VERSION 5.8 ;
BUSBITCHARS "[]" ;
DIVIDERCHAR "/" ;

UNITS
  DATABASE MICRONS 1000 ;
END UNITS

MANUFACTURINGGRID 0.001 ;

SITE asap7sc7p5t
  CLASS CORE ;
  SYMMETRY Y ;
  SIZE 0.054 BY 0.27 ;
END asap7sc7p5t

# ---- RVT filler cells ----
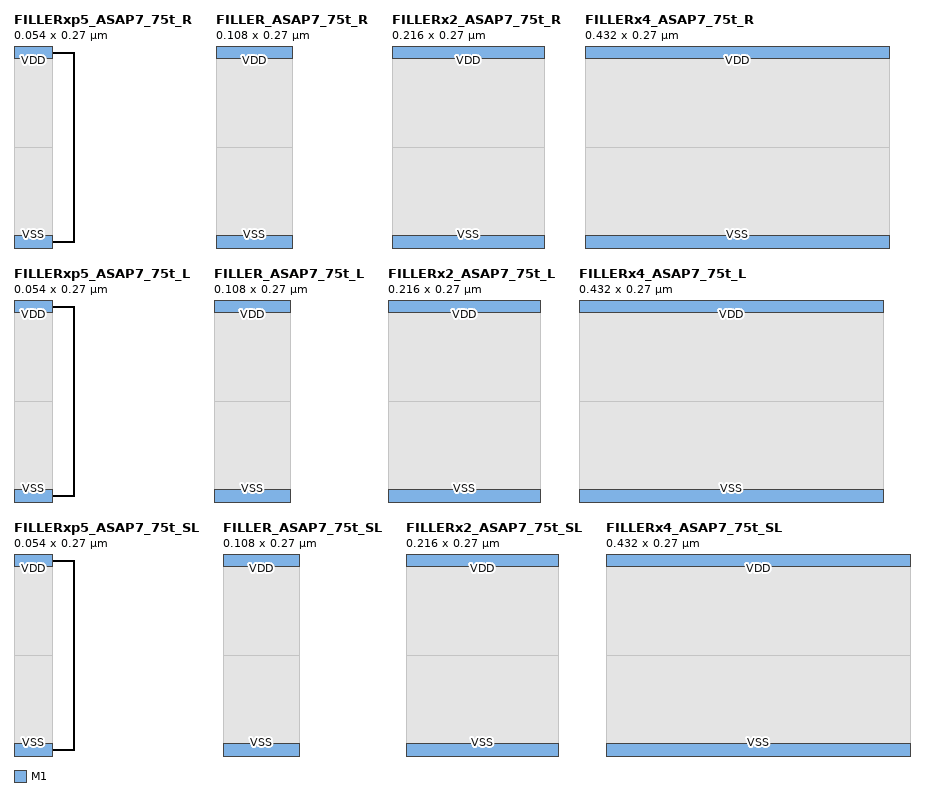
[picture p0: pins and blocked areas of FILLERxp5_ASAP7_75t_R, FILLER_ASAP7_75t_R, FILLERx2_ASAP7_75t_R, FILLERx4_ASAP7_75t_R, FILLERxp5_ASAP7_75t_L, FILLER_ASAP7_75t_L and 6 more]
MACRO FILLERxp5_ASAP7_75t_R
  CLASS CORE SPACER ;
  ORIGIN 0 0 ;
  SIZE 0.054 BY 0.27 ;
  SYMMETRY X Y ;
  SITE asap7sc7p5t ;
  PIN VDD
    DIRECTION INOUT ;
    USE POWER ;
    SHAPE ABUTMENT ;
    PORT
      LAYER M1 ;
        RECT 0 0.261 0.054 0.279 ;
    END
  END VDD
  PIN VSS
    DIRECTION INOUT ;
    USE GROUND ;
    SHAPE ABUTMENT ;
    PORT
      LAYER M1 ;
        RECT 0 -0.009 0.054 0.009 ;
    END
  END VSS
  OBS
    LAYER RVTN ;
      RECT 0 0 0.054 0.135 ;
    LAYER RVTP ;
      RECT 0 0.135 0.054 0.27 ;
  END
END FILLERxp5_ASAP7_75t_R

MACRO FILLER_ASAP7_75t_R
  CLASS CORE SPACER ;
  ORIGIN 0 0 ;
  SIZE 0.108 BY 0.27 ;
  SYMMETRY X Y ;
  SITE asap7sc7p5t ;
  PIN VDD
    DIRECTION INOUT ;
    USE POWER ;
    SHAPE ABUTMENT ;
    PORT
      LAYER M1 ;
        RECT 0 0.261 0.108 0.279 ;
    END
  END VDD
  PIN VSS
    DIRECTION INOUT ;
    USE GROUND ;
    SHAPE ABUTMENT ;
    PORT
      LAYER M1 ;
        RECT 0 -0.009 0.108 0.009 ;
    END
  END VSS
  OBS
    LAYER RVTN ;
      RECT 0 0 0.108 0.135 ;
    LAYER RVTP ;
      RECT 0 0.135 0.108 0.27 ;
  END
END FILLER_ASAP7_75t_R

MACRO FILLERx2_ASAP7_75t_R
  CLASS CORE SPACER ;
  ORIGIN 0 0 ;
  SIZE 0.216 BY 0.27 ;
  SYMMETRY X Y ;
  SITE asap7sc7p5t ;
  PIN VDD
    DIRECTION INOUT ;
    USE POWER ;
    SHAPE ABUTMENT ;
    PORT
      LAYER M1 ;
        RECT 0 0.261 0.216 0.279 ;
    END
  END VDD
  PIN VSS
    DIRECTION INOUT ;
    USE GROUND ;
    SHAPE ABUTMENT ;
    PORT
      LAYER M1 ;
        RECT 0 -0.009 0.216 0.009 ;
    END
  END VSS
  OBS
    LAYER RVTN ;
      RECT 0 0 0.216 0.135 ;
    LAYER RVTP ;
      RECT 0 0.135 0.216 0.27 ;
  END
END FILLERx2_ASAP7_75t_R

MACRO FILLERx4_ASAP7_75t_R
  CLASS CORE SPACER ;
  ORIGIN 0 0 ;
  SIZE 0.432 BY 0.27 ;
  SYMMETRY X Y ;
  SITE asap7sc7p5t ;
  PIN VDD
    DIRECTION INOUT ;
    USE POWER ;
    SHAPE ABUTMENT ;
    PORT
      LAYER M1 ;
        RECT 0 0.261 0.432 0.279 ;
    END
  END VDD
  PIN VSS
    DIRECTION INOUT ;
    USE GROUND ;
    SHAPE ABUTMENT ;
    PORT
      LAYER M1 ;
        RECT 0 -0.009 0.432 0.009 ;
    END
  END VSS
  OBS
    LAYER RVTN ;
      RECT 0 0 0.432 0.135 ;
    LAYER RVTP ;
      RECT 0 0.135 0.432 0.27 ;
  END
END FILLERx4_ASAP7_75t_R

# ---- LVT filler cells ----
MACRO FILLERxp5_ASAP7_75t_L
  CLASS CORE SPACER ;
  ORIGIN 0 0 ;
  SIZE 0.054 BY 0.27 ;
  SYMMETRY X Y ;
  SITE asap7sc7p5t ;
  PIN VDD
    DIRECTION INOUT ;
    USE POWER ;
    SHAPE ABUTMENT ;
    PORT
      LAYER M1 ;
        RECT 0 0.261 0.054 0.279 ;
    END
  END VDD
  PIN VSS
    DIRECTION INOUT ;
    USE GROUND ;
    SHAPE ABUTMENT ;
    PORT
      LAYER M1 ;
        RECT 0 -0.009 0.054 0.009 ;
    END
  END VSS
  OBS
    LAYER LVTN ;
      RECT 0 0 0.054 0.135 ;
    LAYER LVTP ;
      RECT 0 0.135 0.054 0.27 ;
  END
END FILLERxp5_ASAP7_75t_L

MACRO FILLER_ASAP7_75t_L
  CLASS CORE SPACER ;
  ORIGIN 0 0 ;
  SIZE 0.108 BY 0.27 ;
  SYMMETRY X Y ;
  SITE asap7sc7p5t ;
  PIN VDD
    DIRECTION INOUT ;
    USE POWER ;
    SHAPE ABUTMENT ;
    PORT
      LAYER M1 ;
        RECT 0 0.261 0.108 0.279 ;
    END
  END VDD
  PIN VSS
    DIRECTION INOUT ;
    USE GROUND ;
    SHAPE ABUTMENT ;
    PORT
      LAYER M1 ;
        RECT 0 -0.009 0.108 0.009 ;
    END
  END VSS
  OBS
    LAYER LVTN ;
      RECT 0 0 0.108 0.135 ;
    LAYER LVTP ;
      RECT 0 0.135 0.108 0.27 ;
  END
END FILLER_ASAP7_75t_L

MACRO FILLERx2_ASAP7_75t_L
  CLASS CORE SPACER ;
  ORIGIN 0 0 ;
  SIZE 0.216 BY 0.27 ;
  SYMMETRY X Y ;
  SITE asap7sc7p5t ;
  PIN VDD
    DIRECTION INOUT ;
    USE POWER ;
    SHAPE ABUTMENT ;
    PORT
      LAYER M1 ;
        RECT 0 0.261 0.216 0.279 ;
    END
  END VDD
  PIN VSS
    DIRECTION INOUT ;
    USE GROUND ;
    SHAPE ABUTMENT ;
    PORT
      LAYER M1 ;
        RECT 0 -0.009 0.216 0.009 ;
    END
  END VSS
  OBS
    LAYER LVTN ;
      RECT 0 0 0.216 0.135 ;
    LAYER LVTP ;
      RECT 0 0.135 0.216 0.27 ;
  END
END FILLERx2_ASAP7_75t_L

MACRO FILLERx4_ASAP7_75t_L
  CLASS CORE SPACER ;
  ORIGIN 0 0 ;
  SIZE 0.432 BY 0.27 ;
  SYMMETRY X Y ;
  SITE asap7sc7p5t ;
  PIN VDD
    DIRECTION INOUT ;
    USE POWER ;
    SHAPE ABUTMENT ;
    PORT
      LAYER M1 ;
        RECT 0 0.261 0.432 0.279 ;
    END
  END VDD
  PIN VSS
    DIRECTION INOUT ;
    USE GROUND ;
    SHAPE ABUTMENT ;
    PORT
      LAYER M1 ;
        RECT 0 -0.009 0.432 0.009 ;
    END
  END VSS
  OBS
    LAYER LVTN ;
      RECT 0 0 0.432 0.135 ;
    LAYER LVTP ;
      RECT 0 0.135 0.432 0.27 ;
  END
END FILLERx4_ASAP7_75t_L

# ---- SLVT filler cells ----
MACRO FILLERxp5_ASAP7_75t_SL
  CLASS CORE SPACER ;
  ORIGIN 0 0 ;
  SIZE 0.054 BY 0.27 ;
  SYMMETRY X Y ;
  SITE asap7sc7p5t ;
  PIN VDD
    DIRECTION INOUT ;
    USE POWER ;
    SHAPE ABUTMENT ;
    PORT
      LAYER M1 ;
        RECT 0 0.261 0.054 0.279 ;
    END
  END VDD
  PIN VSS
    DIRECTION INOUT ;
    USE GROUND ;
    SHAPE ABUTMENT ;
    PORT
      LAYER M1 ;
        RECT 0 -0.009 0.054 0.009 ;
    END
  END VSS
  OBS
    LAYER SLVTN ;
      RECT 0 0 0.054 0.135 ;
    LAYER SLVTP ;
      RECT 0 0.135 0.054 0.27 ;
  END
END FILLERxp5_ASAP7_75t_SL

MACRO FILLER_ASAP7_75t_SL
  CLASS CORE SPACER ;
  ORIGIN 0 0 ;
  SIZE 0.108 BY 0.27 ;
  SYMMETRY X Y ;
  SITE asap7sc7p5t ;
  PIN VDD
    DIRECTION INOUT ;
    USE POWER ;
    SHAPE ABUTMENT ;
    PORT
      LAYER M1 ;
        RECT 0 0.261 0.108 0.279 ;
    END
  END VDD
  PIN VSS
    DIRECTION INOUT ;
    USE GROUND ;
    SHAPE ABUTMENT ;
    PORT
      LAYER M1 ;
        RECT 0 -0.009 0.108 0.009 ;
    END
  END VSS
  OBS
    LAYER SLVTN ;
      RECT 0 0 0.108 0.135 ;
    LAYER SLVTP ;
      RECT 0 0.135 0.108 0.27 ;
  END
END FILLER_ASAP7_75t_SL

MACRO FILLERx2_ASAP7_75t_SL
  CLASS CORE SPACER ;
  ORIGIN 0 0 ;
  SIZE 0.216 BY 0.27 ;
  SYMMETRY X Y ;
  SITE asap7sc7p5t ;
  PIN VDD
    DIRECTION INOUT ;
    USE POWER ;
    SHAPE ABUTMENT ;
    PORT
      LAYER M1 ;
        RECT 0 0.261 0.216 0.279 ;
    END
  END VDD
  PIN VSS
    DIRECTION INOUT ;
    USE GROUND ;
    SHAPE ABUTMENT ;
    PORT
      LAYER M1 ;
        RECT 0 -0.009 0.216 0.009 ;
    END
  END VSS
  OBS
    LAYER SLVTN ;
      RECT 0 0 0.216 0.135 ;
    LAYER SLVTP ;
      RECT 0 0.135 0.216 0.27 ;
  END
END FILLERx2_ASAP7_75t_SL

MACRO FILLERx4_ASAP7_75t_SL
  CLASS CORE SPACER ;
  ORIGIN 0 0 ;
  SIZE 0.432 BY 0.27 ;
  SYMMETRY X Y ;
  SITE asap7sc7p5t ;
  PIN VDD
    DIRECTION INOUT ;
    USE POWER ;
    SHAPE ABUTMENT ;
    PORT
      LAYER M1 ;
        RECT 0 0.261 0.432 0.279 ;
    END
  END VDD
  PIN VSS
    DIRECTION INOUT ;
    USE GROUND ;
    SHAPE ABUTMENT ;
    PORT
      LAYER M1 ;
        RECT 0 -0.009 0.432 0.009 ;
    END
  END VSS
  OBS
    LAYER SLVTN ;
      RECT 0 0 0.432 0.135 ;
    LAYER SLVTP ;
      RECT 0 0.135 0.432 0.27 ;
  END
END FILLERx4_ASAP7_75t_SL

# ---- ULVT filler cells ----
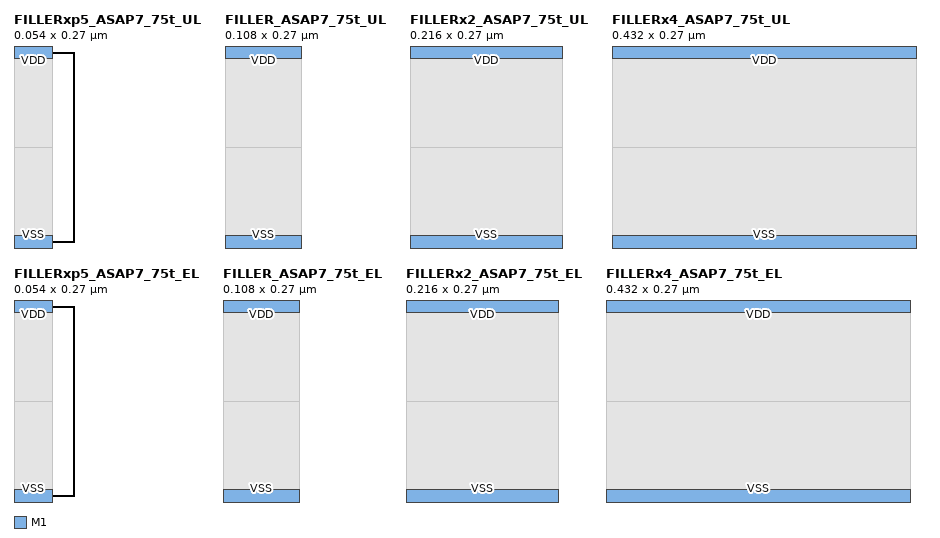
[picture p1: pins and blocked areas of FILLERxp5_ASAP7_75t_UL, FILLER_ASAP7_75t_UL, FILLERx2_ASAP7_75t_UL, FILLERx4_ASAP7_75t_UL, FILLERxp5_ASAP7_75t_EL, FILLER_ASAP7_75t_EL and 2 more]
MACRO FILLERxp5_ASAP7_75t_UL
  CLASS CORE SPACER ;
  ORIGIN 0 0 ;
  SIZE 0.054 BY 0.27 ;
  SYMMETRY X Y ;
  SITE asap7sc7p5t ;
  PIN VDD
    DIRECTION INOUT ;
    USE POWER ;
    SHAPE ABUTMENT ;
    PORT
      LAYER M1 ;
        RECT 0 0.261 0.054 0.279 ;
    END
  END VDD
  PIN VSS
    DIRECTION INOUT ;
    USE GROUND ;
    SHAPE ABUTMENT ;
    PORT
      LAYER M1 ;
        RECT 0 -0.009 0.054 0.009 ;
    END
  END VSS
  OBS
    LAYER ULVTN ;
      RECT 0 0 0.054 0.135 ;
    LAYER ULVTP ;
      RECT 0 0.135 0.054 0.27 ;
  END
END FILLERxp5_ASAP7_75t_UL

MACRO FILLER_ASAP7_75t_UL
  CLASS CORE SPACER ;
  ORIGIN 0 0 ;
  SIZE 0.108 BY 0.27 ;
  SYMMETRY X Y ;
  SITE asap7sc7p5t ;
  PIN VDD
    DIRECTION INOUT ;
    USE POWER ;
    SHAPE ABUTMENT ;
    PORT
      LAYER M1 ;
        RECT 0 0.261 0.108 0.279 ;
    END
  END VDD
  PIN VSS
    DIRECTION INOUT ;
    USE GROUND ;
    SHAPE ABUTMENT ;
    PORT
      LAYER M1 ;
        RECT 0 -0.009 0.108 0.009 ;
    END
  END VSS
  OBS
    LAYER ULVTN ;
      RECT 0 0 0.108 0.135 ;
    LAYER ULVTP ;
      RECT 0 0.135 0.108 0.27 ;
  END
END FILLER_ASAP7_75t_UL

MACRO FILLERx2_ASAP7_75t_UL
  CLASS CORE SPACER ;
  ORIGIN 0 0 ;
  SIZE 0.216 BY 0.27 ;
  SYMMETRY X Y ;
  SITE asap7sc7p5t ;
  PIN VDD
    DIRECTION INOUT ;
    USE POWER ;
    SHAPE ABUTMENT ;
    PORT
      LAYER M1 ;
        RECT 0 0.261 0.216 0.279 ;
    END
  END VDD
  PIN VSS
    DIRECTION INOUT ;
    USE GROUND ;
    SHAPE ABUTMENT ;
    PORT
      LAYER M1 ;
        RECT 0 -0.009 0.216 0.009 ;
    END
  END VSS
  OBS
    LAYER ULVTN ;
      RECT 0 0 0.216 0.135 ;
    LAYER ULVTP ;
      RECT 0 0.135 0.216 0.27 ;
  END
END FILLERx2_ASAP7_75t_UL

MACRO FILLERx4_ASAP7_75t_UL
  CLASS CORE SPACER ;
  ORIGIN 0 0 ;
  SIZE 0.432 BY 0.27 ;
  SYMMETRY X Y ;
  SITE asap7sc7p5t ;
  PIN VDD
    DIRECTION INOUT ;
    USE POWER ;
    SHAPE ABUTMENT ;
    PORT
      LAYER M1 ;
        RECT 0 0.261 0.432 0.279 ;
    END
  END VDD
  PIN VSS
    DIRECTION INOUT ;
    USE GROUND ;
    SHAPE ABUTMENT ;
    PORT
      LAYER M1 ;
        RECT 0 -0.009 0.432 0.009 ;
    END
  END VSS
  OBS
    LAYER ULVTN ;
      RECT 0 0 0.432 0.135 ;
    LAYER ULVTP ;
      RECT 0 0.135 0.432 0.27 ;
  END
END FILLERx4_ASAP7_75t_UL

# ---- ELVT filler cells ----
MACRO FILLERxp5_ASAP7_75t_EL
  CLASS CORE SPACER ;
  ORIGIN 0 0 ;
  SIZE 0.054 BY 0.27 ;
  SYMMETRY X Y ;
  SITE asap7sc7p5t ;
  PIN VDD
    DIRECTION INOUT ;
    USE POWER ;
    SHAPE ABUTMENT ;
    PORT
      LAYER M1 ;
        RECT 0 0.261 0.054 0.279 ;
    END
  END VDD
  PIN VSS
    DIRECTION INOUT ;
    USE GROUND ;
    SHAPE ABUTMENT ;
    PORT
      LAYER M1 ;
        RECT 0 -0.009 0.054 0.009 ;
    END
  END VSS
  OBS
    LAYER ELVTN ;
      RECT 0 0 0.054 0.135 ;
    LAYER ELVTP ;
      RECT 0 0.135 0.054 0.27 ;
  END
END FILLERxp5_ASAP7_75t_EL

MACRO FILLER_ASAP7_75t_EL
  CLASS CORE SPACER ;
  ORIGIN 0 0 ;
  SIZE 0.108 BY 0.27 ;
  SYMMETRY X Y ;
  SITE asap7sc7p5t ;
  PIN VDD
    DIRECTION INOUT ;
    USE POWER ;
    SHAPE ABUTMENT ;
    PORT
      LAYER M1 ;
        RECT 0 0.261 0.108 0.279 ;
    END
  END VDD
  PIN VSS
    DIRECTION INOUT ;
    USE GROUND ;
    SHAPE ABUTMENT ;
    PORT
      LAYER M1 ;
        RECT 0 -0.009 0.108 0.009 ;
    END
  END VSS
  OBS
    LAYER ELVTN ;
      RECT 0 0 0.108 0.135 ;
    LAYER ELVTP ;
      RECT 0 0.135 0.108 0.27 ;
  END
END FILLER_ASAP7_75t_EL

MACRO FILLERx2_ASAP7_75t_EL
  CLASS CORE SPACER ;
  ORIGIN 0 0 ;
  SIZE 0.216 BY 0.27 ;
  SYMMETRY X Y ;
  SITE asap7sc7p5t ;
  PIN VDD
    DIRECTION INOUT ;
    USE POWER ;
    SHAPE ABUTMENT ;
    PORT
      LAYER M1 ;
        RECT 0 0.261 0.216 0.279 ;
    END
  END VDD
  PIN VSS
    DIRECTION INOUT ;
    USE GROUND ;
    SHAPE ABUTMENT ;
    PORT
      LAYER M1 ;
        RECT 0 -0.009 0.216 0.009 ;
    END
  END VSS
  OBS
    LAYER ELVTN ;
      RECT 0 0 0.216 0.135 ;
    LAYER ELVTP ;
      RECT 0 0.135 0.216 0.27 ;
  END
END FILLERx2_ASAP7_75t_EL

MACRO FILLERx4_ASAP7_75t_EL
  CLASS CORE SPACER ;
  ORIGIN 0 0 ;
  SIZE 0.432 BY 0.27 ;
  SYMMETRY X Y ;
  SITE asap7sc7p5t ;
  PIN VDD
    DIRECTION INOUT ;
    USE POWER ;
    SHAPE ABUTMENT ;
    PORT
      LAYER M1 ;
        RECT 0 0.261 0.432 0.279 ;
    END
  END VDD
  PIN VSS
    DIRECTION INOUT ;
    USE GROUND ;
    SHAPE ABUTMENT ;
    PORT
      LAYER M1 ;
        RECT 0 -0.009 0.432 0.009 ;
    END
  END VSS
  OBS
    LAYER ELVTN ;
      RECT 0 0 0.432 0.135 ;
    LAYER ELVTP ;
      RECT 0 0.135 0.432 0.27 ;
  END
END FILLERx4_ASAP7_75t_EL

END LIBRARY
